VERSION 5.7 ;
  NOWIREEXTENSIONATPIN ON ;
  DIVIDERCHAR "/" ;
  BUSBITCHARS "[]" ;
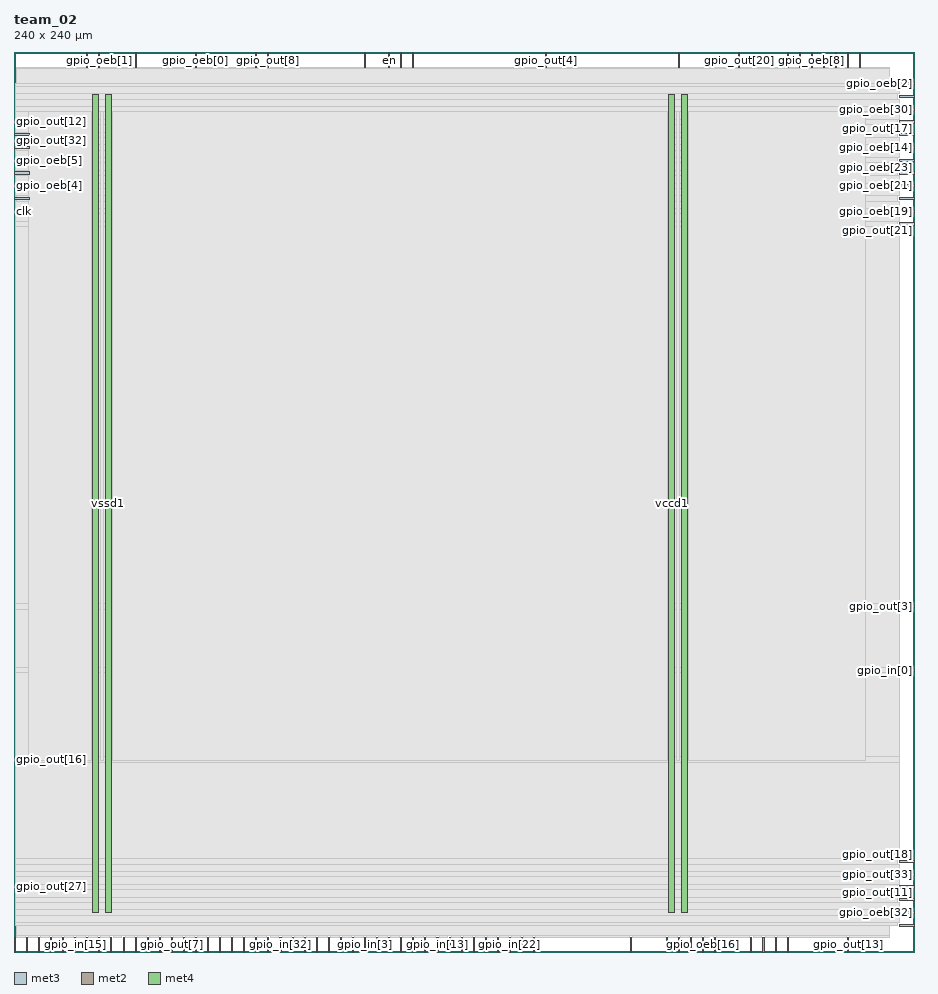
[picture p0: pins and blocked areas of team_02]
MACRO team_02
  CLASS BLOCK ;
  FOREIGN team_02 ;
  ORIGIN 0.000 0.000 ;
  SIZE 240.000 BY 240.000 ;
  PIN clk
    DIRECTION INPUT ;
    USE SIGNAL ;
    ANTENNAGATEAREA 1.286700 ;
    ANTENNADIFFAREA 0.434700 ;
    PORT
      LAYER met3 ;
        RECT 0.000 197.240 4.000 197.840 ;
    END
  END clk
  PIN en
    DIRECTION INPUT ;
    USE SIGNAL ;
    ANTENNAGATEAREA 0.631200 ;
    ANTENNADIFFAREA 0.434700 ;
    PORT
      LAYER met2 ;
        RECT 99.910 236.000 100.190 240.000 ;
    END
  END en
  PIN gpio_in[0]
    DIRECTION INPUT ;
    USE SIGNAL ;
    ANTENNAGATEAREA 0.647700 ;
    ANTENNADIFFAREA 0.434700 ;
    PORT
      LAYER met3 ;
        RECT 236.000 74.840 240.000 75.440 ;
    END
  END gpio_in[0]
  PIN gpio_in[10]
    DIRECTION INPUT ;
    USE SIGNAL ;
    PORT
      LAYER met2 ;
        RECT 125.670 0.000 125.950 4.000 ;
    END
  END gpio_in[10]
  PIN gpio_in[11]
    DIRECTION INPUT ;
    USE SIGNAL ;
    PORT
      LAYER met2 ;
        RECT 9.750 0.000 10.030 4.000 ;
    END
  END gpio_in[11]
  PIN gpio_in[12]
    DIRECTION INPUT ;
    USE SIGNAL ;
    PORT
      LAYER met2 ;
        RECT 35.510 0.000 35.790 4.000 ;
    END
  END gpio_in[12]
  PIN gpio_in[13]
    DIRECTION INPUT ;
    USE SIGNAL ;
    PORT
      LAYER met2 ;
        RECT 112.790 0.000 113.070 4.000 ;
    END
  END gpio_in[13]
  PIN gpio_in[14]
    DIRECTION INPUT ;
    USE SIGNAL ;
    PORT
      LAYER met2 ;
        RECT 38.730 0.000 39.010 4.000 ;
    END
  END gpio_in[14]
  PIN gpio_in[15]
    DIRECTION INPUT ;
    USE SIGNAL ;
    PORT
      LAYER met2 ;
        RECT 16.190 0.000 16.470 4.000 ;
    END
  END gpio_in[15]
  PIN gpio_in[16]
    DIRECTION INPUT ;
    USE SIGNAL ;
    PORT
      LAYER met2 ;
        RECT 128.890 0.000 129.170 4.000 ;
    END
  END gpio_in[16]
  PIN gpio_in[17]
    DIRECTION INPUT ;
    USE SIGNAL ;
    PORT
      LAYER met2 ;
        RECT 29.070 0.000 29.350 4.000 ;
    END
  END gpio_in[17]
  PIN gpio_in[18]
    DIRECTION INPUT ;
    USE SIGNAL ;
    PORT
      LAYER met2 ;
        RECT 3.310 0.000 3.590 4.000 ;
    END
  END gpio_in[18]
  PIN gpio_in[19]
    DIRECTION INPUT ;
    USE SIGNAL ;
    PORT
      LAYER met2 ;
        RECT 138.550 0.000 138.830 4.000 ;
    END
  END gpio_in[19]
  PIN gpio_in[1]
    DIRECTION INPUT ;
    USE SIGNAL ;
    ANTENNAGATEAREA 0.647700 ;
    ANTENNADIFFAREA 0.434700 ;
    PORT
      LAYER met2 ;
        RECT 93.470 236.000 93.750 240.000 ;
    END
  END gpio_in[1]
  PIN gpio_in[20]
    DIRECTION INPUT ;
    USE SIGNAL ;
    PORT
      LAYER met2 ;
        RECT 32.290 0.000 32.570 4.000 ;
    END
  END gpio_in[20]
  PIN gpio_in[21]
    DIRECTION INPUT ;
    USE SIGNAL ;
    PORT
      LAYER met2 ;
        RECT 45.170 0.000 45.450 4.000 ;
    END
  END gpio_in[21]
  PIN gpio_in[22]
    DIRECTION INPUT ;
    USE SIGNAL ;
    PORT
      LAYER met2 ;
        RECT 132.110 0.000 132.390 4.000 ;
    END
  END gpio_in[22]
  PIN gpio_in[23]
    DIRECTION INPUT ;
    USE SIGNAL ;
    PORT
      LAYER met2 ;
        RECT 6.530 0.000 6.810 4.000 ;
    END
  END gpio_in[23]
  PIN gpio_in[24]
    DIRECTION INPUT ;
    USE SIGNAL ;
    PORT
      LAYER met2 ;
        RECT 19.410 0.000 19.690 4.000 ;
    END
  END gpio_in[24]
  PIN gpio_in[25]
    DIRECTION INPUT ;
    USE SIGNAL ;
    PORT
      LAYER met2 ;
        RECT 51.610 0.000 51.890 4.000 ;
    END
  END gpio_in[25]
  PIN gpio_in[26]
    DIRECTION INPUT ;
    USE SIGNAL ;
    PORT
      LAYER met2 ;
        RECT 0.090 0.000 0.370 4.000 ;
    END
  END gpio_in[26]
  PIN gpio_in[27]
    DIRECTION INPUT ;
    USE SIGNAL ;
    PORT
      LAYER met2 ;
        RECT 99.910 0.000 100.190 4.000 ;
    END
  END gpio_in[27]
  PIN gpio_in[28]
    DIRECTION INPUT ;
    USE SIGNAL ;
    PORT
      LAYER met2 ;
        RECT 77.370 0.000 77.650 4.000 ;
    END
  END gpio_in[28]
  PIN gpio_in[29]
    DIRECTION INPUT ;
    USE SIGNAL ;
    PORT
      LAYER met2 ;
        RECT 12.970 0.000 13.250 4.000 ;
    END
  END gpio_in[29]
  PIN gpio_in[2]
    DIRECTION INPUT ;
    USE SIGNAL ;
    ANTENNAGATEAREA 0.631200 ;
    ANTENNADIFFAREA 0.434700 ;
    PORT
      LAYER met2 ;
        RECT 106.350 236.000 106.630 240.000 ;
    END
  END gpio_in[2]
  PIN gpio_in[30]
    DIRECTION INPUT ;
    USE SIGNAL ;
    PORT
      LAYER met2 ;
        RECT 135.330 0.000 135.610 4.000 ;
    END
  END gpio_in[30]
  PIN gpio_in[31]
    DIRECTION INPUT ;
    USE SIGNAL ;
    PORT
      LAYER met2 ;
        RECT 74.150 0.000 74.430 4.000 ;
    END
  END gpio_in[31]
  PIN gpio_in[32]
    DIRECTION INPUT ;
    USE SIGNAL ;
    PORT
      LAYER met2 ;
        RECT 70.930 0.000 71.210 4.000 ;
    END
  END gpio_in[32]
  PIN gpio_in[33]
    DIRECTION INPUT ;
    USE SIGNAL ;
    PORT
      LAYER met2 ;
        RECT 106.350 0.000 106.630 4.000 ;
    END
  END gpio_in[33]
  PIN gpio_in[3]
    DIRECTION INPUT ;
    USE SIGNAL ;
    PORT
      LAYER met2 ;
        RECT 93.470 0.000 93.750 4.000 ;
    END
  END gpio_in[3]
  PIN gpio_in[4]
    DIRECTION INPUT ;
    USE SIGNAL ;
    PORT
      LAYER met2 ;
        RECT 80.590 0.000 80.870 4.000 ;
    END
  END gpio_in[4]
  PIN gpio_in[5]
    DIRECTION INPUT ;
    USE SIGNAL ;
    PORT
      LAYER met2 ;
        RECT 83.810 0.000 84.090 4.000 ;
    END
  END gpio_in[5]
  PIN gpio_in[6]
    DIRECTION INPUT ;
    USE SIGNAL ;
    PORT
      LAYER met2 ;
        RECT 87.030 0.000 87.310 4.000 ;
    END
  END gpio_in[6]
  PIN gpio_in[7]
    DIRECTION INPUT ;
    USE SIGNAL ;
    PORT
      LAYER met2 ;
        RECT 90.250 0.000 90.530 4.000 ;
    END
  END gpio_in[7]
  PIN gpio_in[8]
    DIRECTION INPUT ;
    USE SIGNAL ;
    PORT
      LAYER met2 ;
        RECT 109.570 0.000 109.850 4.000 ;
    END
  END gpio_in[8]
  PIN gpio_in[9]
    DIRECTION INPUT ;
    USE SIGNAL ;
    PORT
      LAYER met2 ;
        RECT 96.690 0.000 96.970 4.000 ;
    END
  END gpio_in[9]
  PIN gpio_oeb[0]
    DIRECTION OUTPUT ;
    USE SIGNAL ;
    PORT
      LAYER met2 ;
        RECT 48.390 236.000 48.670 240.000 ;
    END
  END gpio_oeb[0]
  PIN gpio_oeb[10]
    DIRECTION OUTPUT ;
    USE SIGNAL ;
    PORT
      LAYER met2 ;
        RECT 54.830 0.000 55.110 4.000 ;
    END
  END gpio_oeb[10]
  PIN gpio_oeb[11]
    DIRECTION OUTPUT ;
    USE SIGNAL ;
    PORT
      LAYER met2 ;
        RECT 206.170 236.000 206.450 240.000 ;
    END
  END gpio_oeb[11]
  PIN gpio_oeb[12]
    DIRECTION OUTPUT ;
    USE SIGNAL ;
    PORT
      LAYER met2 ;
        RECT 58.050 0.000 58.330 4.000 ;
    END
  END gpio_oeb[12]
  PIN gpio_oeb[13]
    DIRECTION OUTPUT ;
    USE SIGNAL ;
    PORT
      LAYER met3 ;
        RECT 236.000 6.840 240.000 7.440 ;
    END
  END gpio_oeb[13]
  PIN gpio_oeb[14]
    DIRECTION OUTPUT ;
    USE SIGNAL ;
    PORT
      LAYER met3 ;
        RECT 236.000 214.240 240.000 214.840 ;
    END
  END gpio_oeb[14]
  PIN gpio_oeb[15]
    DIRECTION OUTPUT ;
    USE SIGNAL ;
    PORT
      LAYER met2 ;
        RECT 119.230 0.000 119.510 4.000 ;
    END
  END gpio_oeb[15]
  PIN gpio_oeb[16]
    DIRECTION OUTPUT ;
    USE SIGNAL ;
    PORT
      LAYER met2 ;
        RECT 183.630 0.000 183.910 4.000 ;
    END
  END gpio_oeb[16]
  PIN gpio_oeb[17]
    DIRECTION OUTPUT ;
    USE SIGNAL ;
    PORT
      LAYER met2 ;
        RECT 64.490 0.000 64.770 4.000 ;
    END
  END gpio_oeb[17]
  PIN gpio_oeb[18]
    DIRECTION OUTPUT ;
    USE SIGNAL ;
    PORT
      LAYER met2 ;
        RECT 209.390 236.000 209.670 240.000 ;
    END
  END gpio_oeb[18]
  PIN gpio_oeb[19]
    DIRECTION OUTPUT ;
    USE SIGNAL ;
    PORT
      LAYER met3 ;
        RECT 236.000 197.240 240.000 197.840 ;
    END
  END gpio_oeb[19]
  PIN gpio_oeb[1]
    DIRECTION OUTPUT ;
    USE SIGNAL ;
    PORT
      LAYER met2 ;
        RECT 22.630 236.000 22.910 240.000 ;
    END
  END gpio_oeb[1]
  PIN gpio_oeb[20]
    DIRECTION OUTPUT ;
    USE SIGNAL ;
    PORT
      LAYER met2 ;
        RECT 196.510 0.000 196.790 4.000 ;
    END
  END gpio_oeb[20]
  PIN gpio_oeb[21]
    DIRECTION OUTPUT ;
    USE SIGNAL ;
    PORT
      LAYER met3 ;
        RECT 236.000 204.040 240.000 204.640 ;
    END
  END gpio_oeb[21]
  PIN gpio_oeb[22]
    DIRECTION OUTPUT ;
    USE SIGNAL ;
    PORT
      LAYER met2 ;
        RECT 225.490 236.000 225.770 240.000 ;
    END
  END gpio_oeb[22]
  PIN gpio_oeb[23]
    DIRECTION OUTPUT ;
    USE SIGNAL ;
    PORT
      LAYER met3 ;
        RECT 236.000 210.840 240.000 211.440 ;
    END
  END gpio_oeb[23]
  PIN gpio_oeb[24]
    DIRECTION OUTPUT ;
    USE SIGNAL ;
    PORT
      LAYER met2 ;
        RECT 103.130 0.000 103.410 4.000 ;
    END
  END gpio_oeb[24]
  PIN gpio_oeb[25]
    DIRECTION OUTPUT ;
    USE SIGNAL ;
    PORT
      LAYER met2 ;
        RECT 164.310 0.000 164.590 4.000 ;
    END
  END gpio_oeb[25]
  PIN gpio_oeb[26]
    DIRECTION OUTPUT ;
    USE SIGNAL ;
    PORT
      LAYER met2 ;
        RECT 67.710 0.000 67.990 4.000 ;
    END
  END gpio_oeb[26]
  PIN gpio_oeb[27]
    DIRECTION OUTPUT ;
    USE SIGNAL ;
    PORT
      LAYER met3 ;
        RECT 236.000 217.640 240.000 218.240 ;
    END
  END gpio_oeb[27]
  PIN gpio_oeb[28]
    DIRECTION OUTPUT ;
    USE SIGNAL ;
    PORT
      LAYER met3 ;
        RECT 236.000 200.640 240.000 201.240 ;
    END
  END gpio_oeb[28]
  PIN gpio_oeb[29]
    DIRECTION OUTPUT ;
    USE SIGNAL ;
    PORT
      LAYER met3 ;
        RECT 0.000 200.640 4.000 201.240 ;
    END
  END gpio_oeb[29]
  PIN gpio_oeb[2]
    DIRECTION OUTPUT ;
    USE SIGNAL ;
    PORT
      LAYER met3 ;
        RECT 236.000 231.240 240.000 231.840 ;
    END
  END gpio_oeb[2]
  PIN gpio_oeb[30]
    DIRECTION OUTPUT ;
    USE SIGNAL ;
    PORT
      LAYER met3 ;
        RECT 236.000 224.440 240.000 225.040 ;
    END
  END gpio_oeb[30]
  PIN gpio_oeb[31]
    DIRECTION OUTPUT ;
    USE SIGNAL ;
    PORT
      LAYER met2 ;
        RECT 219.050 236.000 219.330 240.000 ;
    END
  END gpio_oeb[31]
  PIN gpio_oeb[32]
    DIRECTION OUTPUT ;
    USE SIGNAL ;
    PORT
      LAYER met3 ;
        RECT 236.000 10.240 240.000 10.840 ;
    END
  END gpio_oeb[32]
  PIN gpio_oeb[33]
    DIRECTION OUTPUT ;
    USE SIGNAL ;
    PORT
      LAYER met2 ;
        RECT 199.730 0.000 200.010 4.000 ;
    END
  END gpio_oeb[33]
  PIN gpio_oeb[3]
    DIRECTION OUTPUT ;
    USE SIGNAL ;
    PORT
      LAYER met2 ;
        RECT 61.270 0.000 61.550 4.000 ;
    END
  END gpio_oeb[3]
  PIN gpio_oeb[4]
    DIRECTION OUTPUT ;
    USE SIGNAL ;
    PORT
      LAYER met3 ;
        RECT 0.000 204.040 4.000 204.640 ;
    END
  END gpio_oeb[4]
  PIN gpio_oeb[5]
    DIRECTION OUTPUT ;
    USE SIGNAL ;
    PORT
      LAYER met3 ;
        RECT 0.000 210.840 4.000 211.440 ;
    END
  END gpio_oeb[5]
  PIN gpio_oeb[6]
    DIRECTION OUTPUT ;
    USE SIGNAL ;
    PORT
      LAYER met3 ;
        RECT 236.000 17.040 240.000 17.640 ;
    END
  END gpio_oeb[6]
  PIN gpio_oeb[7]
    DIRECTION OUTPUT ;
    USE SIGNAL ;
    PORT
      LAYER met2 ;
        RECT 64.490 236.000 64.770 240.000 ;
    END
  END gpio_oeb[7]
  PIN gpio_oeb[8]
    DIRECTION OUTPUT ;
    USE SIGNAL ;
    PORT
      LAYER met2 ;
        RECT 212.610 236.000 212.890 240.000 ;
    END
  END gpio_oeb[8]
  PIN gpio_oeb[9]
    DIRECTION OUTPUT ;
    USE SIGNAL ;
    PORT
      LAYER met2 ;
        RECT 122.450 0.000 122.730 4.000 ;
    END
  END gpio_oeb[9]
  PIN gpio_out[0]
    DIRECTION OUTPUT ;
    USE SIGNAL ;
    PORT
      LAYER met3 ;
        RECT 0.000 207.440 4.000 208.040 ;
    END
  END gpio_out[0]
  PIN gpio_out[10]
    DIRECTION OUTPUT ;
    USE SIGNAL ;
    PORT
      LAYER met2 ;
        RECT 180.410 0.000 180.690 4.000 ;
    END
  END gpio_out[10]
  PIN gpio_out[11]
    DIRECTION OUTPUT ;
    USE SIGNAL ;
    PORT
      LAYER met3 ;
        RECT 236.000 13.640 240.000 14.240 ;
    END
  END gpio_out[11]
  PIN gpio_out[12]
    DIRECTION OUTPUT ;
    USE SIGNAL ;
    PORT
      LAYER met3 ;
        RECT 0.000 221.040 4.000 221.640 ;
    END
  END gpio_out[12]
  PIN gpio_out[13]
    DIRECTION OUTPUT ;
    USE SIGNAL ;
    PORT
      LAYER met2 ;
        RECT 222.270 0.000 222.550 4.000 ;
    END
  END gpio_out[13]
  PIN gpio_out[14]
    DIRECTION OUTPUT ;
    USE SIGNAL ;
    PORT
      LAYER met2 ;
        RECT 32.290 236.000 32.570 240.000 ;
    END
  END gpio_out[14]
  PIN gpio_out[15]
    DIRECTION OUTPUT ;
    USE SIGNAL ;
    PORT
      LAYER met2 ;
        RECT 22.630 0.000 22.910 4.000 ;
    END
  END gpio_out[15]
  PIN gpio_out[16]
    DIRECTION OUTPUT ;
    USE SIGNAL ;
    PORT
      LAYER met3 ;
        RECT 0.000 51.040 4.000 51.640 ;
    END
  END gpio_out[16]
  PIN gpio_out[17]
    DIRECTION OUTPUT ;
    USE SIGNAL ;
    PORT
      LAYER met3 ;
        RECT 236.000 221.040 240.000 221.640 ;
    END
  END gpio_out[17]
  PIN gpio_out[18]
    DIRECTION OUTPUT ;
    USE SIGNAL ;
    PORT
      LAYER met3 ;
        RECT 236.000 23.840 240.000 24.440 ;
    END
  END gpio_out[18]
  PIN gpio_out[19]
    DIRECTION OUTPUT ;
    USE SIGNAL ;
    PORT
      LAYER met2 ;
        RECT 215.830 236.000 216.110 240.000 ;
    END
  END gpio_out[19]
  PIN gpio_out[1]
    DIRECTION OUTPUT ;
    USE SIGNAL ;
    PORT
      LAYER met2 ;
        RECT 186.850 0.000 187.130 4.000 ;
    END
  END gpio_out[1]
  PIN gpio_out[20]
    DIRECTION OUTPUT ;
    USE SIGNAL ;
    PORT
      LAYER met2 ;
        RECT 193.290 236.000 193.570 240.000 ;
    END
  END gpio_out[20]
  PIN gpio_out[21]
    DIRECTION OUTPUT ;
    USE SIGNAL ;
    PORT
      LAYER met3 ;
        RECT 236.000 193.840 240.000 194.440 ;
    END
  END gpio_out[21]
  PIN gpio_out[22]
    DIRECTION OUTPUT ;
    USE SIGNAL ;
    PORT
      LAYER met2 ;
        RECT 177.190 236.000 177.470 240.000 ;
    END
  END gpio_out[22]
  PIN gpio_out[23]
    DIRECTION OUTPUT ;
    USE SIGNAL ;
    PORT
      LAYER met2 ;
        RECT 202.950 0.000 203.230 4.000 ;
    END
  END gpio_out[23]
  PIN gpio_out[24]
    DIRECTION OUTPUT ;
    USE SIGNAL ;
    PORT
      LAYER met3 ;
        RECT 236.000 227.840 240.000 228.440 ;
    END
  END gpio_out[24]
  PIN gpio_out[25]
    DIRECTION OUTPUT ;
    USE SIGNAL ;
    PORT
      LAYER met3 ;
        RECT 0.000 217.640 4.000 218.240 ;
    END
  END gpio_out[25]
  PIN gpio_out[26]
    DIRECTION OUTPUT ;
    USE SIGNAL ;
    PORT
      LAYER met2 ;
        RECT 48.390 0.000 48.670 4.000 ;
    END
  END gpio_out[26]
  PIN gpio_out[27]
    DIRECTION OUTPUT ;
    USE SIGNAL ;
    PORT
      LAYER met3 ;
        RECT 0.000 17.040 4.000 17.640 ;
    END
  END gpio_out[27]
  PIN gpio_out[28]
    DIRECTION OUTPUT ;
    USE SIGNAL ;
    PORT
      LAYER met2 ;
        RECT 19.410 236.000 19.690 240.000 ;
    END
  END gpio_out[28]
  PIN gpio_out[29]
    DIRECTION OUTPUT ;
    USE SIGNAL ;
    PORT
      LAYER met2 ;
        RECT 177.190 0.000 177.470 4.000 ;
    END
  END gpio_out[29]
  PIN gpio_out[2]
    DIRECTION OUTPUT ;
    USE SIGNAL ;
    PORT
      LAYER met2 ;
        RECT 116.010 0.000 116.290 4.000 ;
    END
  END gpio_out[2]
  PIN gpio_out[30]
    DIRECTION OUTPUT ;
    USE SIGNAL ;
    PORT
      LAYER met2 ;
        RECT 222.270 236.000 222.550 240.000 ;
    END
  END gpio_out[30]
  PIN gpio_out[31]
    DIRECTION OUTPUT ;
    USE SIGNAL ;
    PORT
      LAYER met2 ;
        RECT 173.970 0.000 174.250 4.000 ;
    END
  END gpio_out[31]
  PIN gpio_out[32]
    DIRECTION OUTPUT ;
    USE SIGNAL ;
    PORT
      LAYER met3 ;
        RECT 0.000 214.240 4.000 214.840 ;
    END
  END gpio_out[32]
  PIN gpio_out[33]
    DIRECTION OUTPUT ;
    USE SIGNAL ;
    PORT
      LAYER met3 ;
        RECT 236.000 20.440 240.000 21.040 ;
    END
  END gpio_out[33]
  PIN gpio_out[3]
    DIRECTION OUTPUT ;
    USE SIGNAL ;
    ANTENNADIFFAREA 0.445500 ;
    PORT
      LAYER met3 ;
        RECT 236.000 91.840 240.000 92.440 ;
    END
  END gpio_out[3]
  PIN gpio_out[4]
    DIRECTION OUTPUT ;
    USE SIGNAL ;
    ANTENNADIFFAREA 0.445500 ;
    PORT
      LAYER met2 ;
        RECT 141.770 236.000 142.050 240.000 ;
    END
  END gpio_out[4]
  PIN gpio_out[5]
    DIRECTION OUTPUT ;
    USE SIGNAL ;
    PORT
      LAYER met2 ;
        RECT 206.170 0.000 206.450 4.000 ;
    END
  END gpio_out[5]
  PIN gpio_out[6]
    DIRECTION OUTPUT ;
    USE SIGNAL ;
    PORT
      LAYER met3 ;
        RECT 236.000 207.440 240.000 208.040 ;
    END
  END gpio_out[6]
  PIN gpio_out[7]
    DIRECTION OUTPUT ;
    USE SIGNAL ;
    PORT
      LAYER met2 ;
        RECT 41.950 0.000 42.230 4.000 ;
    END
  END gpio_out[7]
  PIN gpio_out[8]
    DIRECTION OUTPUT ;
    USE SIGNAL ;
    PORT
      LAYER met2 ;
        RECT 67.710 236.000 67.990 240.000 ;
    END
  END gpio_out[8]
  PIN gpio_out[9]
    DIRECTION OUTPUT ;
    USE SIGNAL ;
    PORT
      LAYER met2 ;
        RECT 25.850 0.000 26.130 4.000 ;
    END
  END gpio_out[9]
  PIN nrst
    DIRECTION INPUT ;
    USE SIGNAL ;
    ANTENNAGATEAREA 0.631200 ;
    ANTENNADIFFAREA 0.434700 ;
    PORT
      LAYER met2 ;
        RECT 103.130 236.000 103.410 240.000 ;
    END
  END nrst
  PIN vccd1
    DIRECTION INOUT ;
    USE POWER ;
    PORT
      LAYER met4 ;
        RECT 21.040 10.640 22.640 228.720 ;
    END
    PORT
      LAYER met4 ;
        RECT 174.640 10.640 176.240 228.720 ;
    END
  END vccd1
  PIN vssd1
    DIRECTION INOUT ;
    USE GROUND ;
    PORT
      LAYER met4 ;
        RECT 24.340 10.640 25.940 228.720 ;
    END
    PORT
      LAYER met4 ;
        RECT 177.940 10.640 179.540 228.720 ;
    END
  END vssd1
  OBS
      LAYER nwell ;
        RECT 5.330 10.760 234.330 228.600 ;
      LAYER li1 ;
        RECT 5.520 10.795 234.140 228.565 ;
      LAYER met1 ;
        RECT 0.530 10.640 234.440 228.720 ;
      LAYER met2 ;
        RECT 0.550 235.720 19.130 236.000 ;
        RECT 19.970 235.720 22.350 236.000 ;
        RECT 23.190 235.720 32.010 236.000 ;
        RECT 32.850 235.720 48.110 236.000 ;
        RECT 48.950 235.720 64.210 236.000 ;
        RECT 65.050 235.720 67.430 236.000 ;
        RECT 68.270 235.720 93.190 236.000 ;
        RECT 94.030 235.720 99.630 236.000 ;
        RECT 100.470 235.720 102.850 236.000 ;
        RECT 103.690 235.720 106.070 236.000 ;
        RECT 106.910 235.720 141.490 236.000 ;
        RECT 142.330 235.720 176.910 236.000 ;
        RECT 177.750 235.720 193.010 236.000 ;
        RECT 193.850 235.720 205.890 236.000 ;
        RECT 206.730 235.720 209.110 236.000 ;
        RECT 209.950 235.720 212.330 236.000 ;
        RECT 213.170 235.720 215.550 236.000 ;
        RECT 216.390 235.720 218.770 236.000 ;
        RECT 219.610 235.720 221.990 236.000 ;
        RECT 222.830 235.720 225.210 236.000 ;
        RECT 226.050 235.720 233.590 236.000 ;
        RECT 0.550 4.280 233.590 235.720 ;
        RECT 0.650 4.000 3.030 4.280 ;
        RECT 3.870 4.000 6.250 4.280 ;
        RECT 7.090 4.000 9.470 4.280 ;
        RECT 10.310 4.000 12.690 4.280 ;
        RECT 13.530 4.000 15.910 4.280 ;
        RECT 16.750 4.000 19.130 4.280 ;
        RECT 19.970 4.000 22.350 4.280 ;
        RECT 23.190 4.000 25.570 4.280 ;
        RECT 26.410 4.000 28.790 4.280 ;
        RECT 29.630 4.000 32.010 4.280 ;
        RECT 32.850 4.000 35.230 4.280 ;
        RECT 36.070 4.000 38.450 4.280 ;
        RECT 39.290 4.000 41.670 4.280 ;
        RECT 42.510 4.000 44.890 4.280 ;
        RECT 45.730 4.000 48.110 4.280 ;
        RECT 48.950 4.000 51.330 4.280 ;
        RECT 52.170 4.000 54.550 4.280 ;
        RECT 55.390 4.000 57.770 4.280 ;
        RECT 58.610 4.000 60.990 4.280 ;
        RECT 61.830 4.000 64.210 4.280 ;
        RECT 65.050 4.000 67.430 4.280 ;
        RECT 68.270 4.000 70.650 4.280 ;
        RECT 71.490 4.000 73.870 4.280 ;
        RECT 74.710 4.000 77.090 4.280 ;
        RECT 77.930 4.000 80.310 4.280 ;
        RECT 81.150 4.000 83.530 4.280 ;
        RECT 84.370 4.000 86.750 4.280 ;
        RECT 87.590 4.000 89.970 4.280 ;
        RECT 90.810 4.000 93.190 4.280 ;
        RECT 94.030 4.000 96.410 4.280 ;
        RECT 97.250 4.000 99.630 4.280 ;
        RECT 100.470 4.000 102.850 4.280 ;
        RECT 103.690 4.000 106.070 4.280 ;
        RECT 106.910 4.000 109.290 4.280 ;
        RECT 110.130 4.000 112.510 4.280 ;
        RECT 113.350 4.000 115.730 4.280 ;
        RECT 116.570 4.000 118.950 4.280 ;
        RECT 119.790 4.000 122.170 4.280 ;
        RECT 123.010 4.000 125.390 4.280 ;
        RECT 126.230 4.000 128.610 4.280 ;
        RECT 129.450 4.000 131.830 4.280 ;
        RECT 132.670 4.000 135.050 4.280 ;
        RECT 135.890 4.000 138.270 4.280 ;
        RECT 139.110 4.000 164.030 4.280 ;
        RECT 164.870 4.000 173.690 4.280 ;
        RECT 174.530 4.000 176.910 4.280 ;
        RECT 177.750 4.000 180.130 4.280 ;
        RECT 180.970 4.000 183.350 4.280 ;
        RECT 184.190 4.000 186.570 4.280 ;
        RECT 187.410 4.000 196.230 4.280 ;
        RECT 197.070 4.000 199.450 4.280 ;
        RECT 200.290 4.000 202.670 4.280 ;
        RECT 203.510 4.000 205.890 4.280 ;
        RECT 206.730 4.000 221.990 4.280 ;
        RECT 222.830 4.000 233.590 4.280 ;
      LAYER met3 ;
        RECT 0.525 230.840 235.600 231.705 ;
        RECT 0.525 228.840 236.000 230.840 ;
        RECT 0.525 227.440 235.600 228.840 ;
        RECT 0.525 225.440 236.000 227.440 ;
        RECT 0.525 224.040 235.600 225.440 ;
        RECT 0.525 222.040 236.000 224.040 ;
        RECT 4.400 220.640 235.600 222.040 ;
        RECT 0.525 218.640 236.000 220.640 ;
        RECT 4.400 217.240 235.600 218.640 ;
        RECT 0.525 215.240 236.000 217.240 ;
        RECT 4.400 213.840 235.600 215.240 ;
        RECT 0.525 211.840 236.000 213.840 ;
        RECT 4.400 210.440 235.600 211.840 ;
        RECT 0.525 208.440 236.000 210.440 ;
        RECT 4.400 207.040 235.600 208.440 ;
        RECT 0.525 205.040 236.000 207.040 ;
        RECT 4.400 203.640 235.600 205.040 ;
        RECT 0.525 201.640 236.000 203.640 ;
        RECT 4.400 200.240 235.600 201.640 ;
        RECT 0.525 198.240 236.000 200.240 ;
        RECT 4.400 196.840 235.600 198.240 ;
        RECT 0.525 194.840 236.000 196.840 ;
        RECT 0.525 193.440 235.600 194.840 ;
        RECT 0.525 92.840 236.000 193.440 ;
        RECT 0.525 91.440 235.600 92.840 ;
        RECT 0.525 75.840 236.000 91.440 ;
        RECT 0.525 74.440 235.600 75.840 ;
        RECT 0.525 52.040 236.000 74.440 ;
        RECT 4.400 50.640 236.000 52.040 ;
        RECT 0.525 24.840 236.000 50.640 ;
        RECT 0.525 23.440 235.600 24.840 ;
        RECT 0.525 21.440 236.000 23.440 ;
        RECT 0.525 20.040 235.600 21.440 ;
        RECT 0.525 18.040 236.000 20.040 ;
        RECT 4.400 16.640 235.600 18.040 ;
        RECT 0.525 14.640 236.000 16.640 ;
        RECT 0.525 13.240 235.600 14.640 ;
        RECT 0.525 11.240 236.000 13.240 ;
        RECT 0.525 9.840 235.600 11.240 ;
        RECT 0.525 7.840 236.000 9.840 ;
        RECT 0.525 6.975 235.600 7.840 ;
      LAYER met4 ;
        RECT 3.975 51.175 20.640 224.225 ;
        RECT 23.040 51.175 23.940 224.225 ;
        RECT 26.340 51.175 174.240 224.225 ;
        RECT 176.640 51.175 177.540 224.225 ;
        RECT 179.940 51.175 226.945 224.225 ;
  END
END team_02
END LIBRARY

